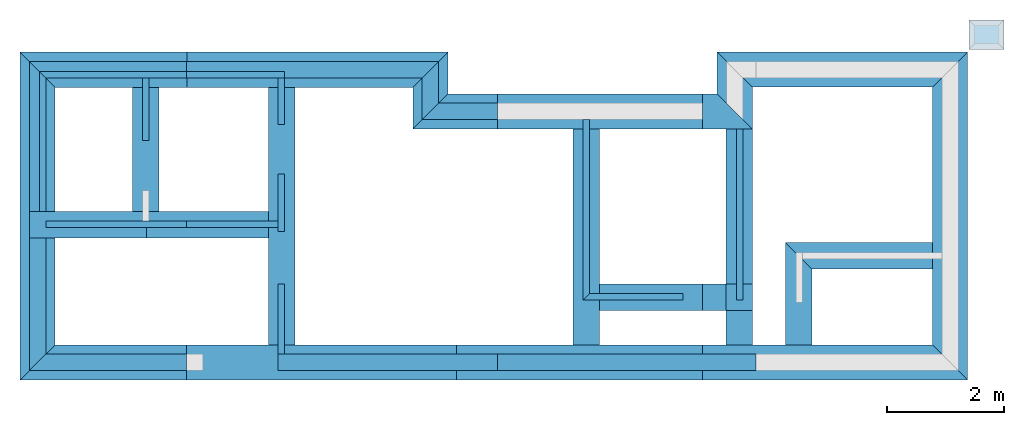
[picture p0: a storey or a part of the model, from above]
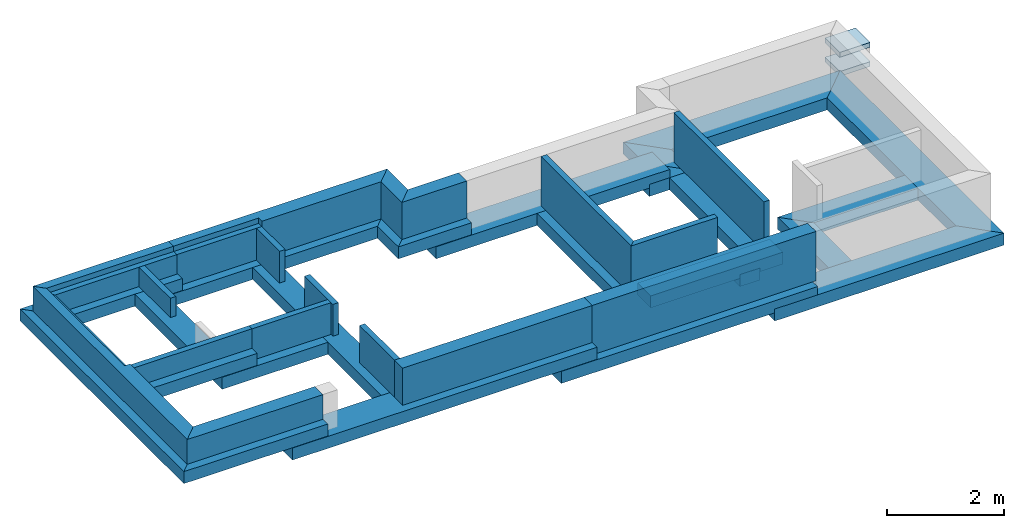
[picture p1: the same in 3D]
Properties of the parts of a building model (IFC2X3)

# File
Description: ViewDefinition [CoordinationView_V2.0], Option [Visible elements;Keep GUIDs;2D Elems;All Domain;All elements;All struct.;scale:100.000000;CSG:BREP;Junction:BREP;Comp. slab:BREPBuilding element parts;]
File name: /Users/johnm/Documents/Master/Projects/AIQS Costing Model/MOD Model/FINAL 2014/IFC Exports/Z01 Full Model.ifc
Time: 2014-02-20T13:36:24
Author: Architect
Organization: AUSTRALIAN INSTITUE OF QUANITY SURVEYERS
Written by: PreProc - EDM 5.0
Made in: IFC file generated by Graphisoft ArchiCAD-64 17.0.0 AUS FULL Macintosh version (IFC2x3 add-on version: 5019 AUS FULL).
Authorization: The authorising person

# IfcProject, Detailed Building Measurement
Phase: PRELIMINARY

# IfcSite, Lot 1. East Hills
RefLatitude: -33, -52, 0, 0; RefLongitude: 151, 13, 0, 0; RefElevation: 0 mm; LandTitleNumber: SP999999

# IfcBuildingStorey (4)
In: Proposed Units 7 & 8
Name | LongName | Elevation (mm)
Foundation | ACID00000002-0000-0000-0000-000000000000 | 1750
Ground | ACID00000003-0000-0000-0000-000000000000 | 3202
Level 1 | ACID00000004-0000-0000-0000-000000000000 | 5859
Roof | ACID00000005-0000-0000-0000-000000000000 | 8395

# IfcBeam: Concrete Reinforced 450 x 250 (10)
In: Foundation
Material: Concrete Reinforced
AC_Pset_RenovationAndPhasing - Renovation Status: Existing
Pset_BeamCommon - Reference: Concrete Reinforced 450 x 250
Name
2 x FT-TYP-A06 - Concrete Reinforced - Beam******************************
FT-TYP-A04 - Concrete Reinforced - Beam******************************
FT-TYP-A00 - Concrete Reinforced - Beam******************************
FT-TYP-A01 - Concrete Reinforced - Beam******************************
FT-TYP-A08 - Concrete Reinforced - Beam******************************
FT-TYP-A02 - Concrete Reinforced - Beam******************************
FT-TYP-A05 - Concrete Reinforced - Beam******************************
2 x FT-TYP-A07 - Concrete Reinforced - Beam******************************

# IfcBeam: Concrete Reinforced 50 x 104 (2)
In: Level 1
Material: Concrete Reinforced
AC_Pset_RenovationAndPhasing - Renovation Status: Existing
Pset_BeamCommon - Reference: Concrete Reinforced 50 x 104

# IfcBeam: Concrete Reinforced 600 x 250 (14)
In: Foundation
Material: Concrete Reinforced
AC_Pset_RenovationAndPhasing - Renovation Status: Existing
Pset_BeamCommon - Reference: Concrete Reinforced 600 x 250
Name
FT-TYP-A02 - Concrete Reinforced - Beam******************************
FT-TYP-A14 - Concrete Reinforced - Beam******************************
FT-TYP-A10 - Concrete Reinforced - Beam******************************
FT-TYP-B00 - Concrete Reinforced - Beam******************************
FT-TYP-B01 - Concrete Reinforced - Beam******************************
FT-TYP-B02 - Concrete Reinforced - Beam******************************
FT-TYP-B03 - Concrete Reinforced - Beam******************************
FT-TYP-B09 - Concrete Reinforced - Beam******************************
FT-TYP-B11 - Concrete Reinforced - Beam******************************
FT-TYP-B12 - Concrete Reinforced - Beam******************************
FT-TYP-B13 - Concrete Reinforced - Beam******************************
FT-TYP-A13 - Concrete Reinforced - Beam******************************
FT-TYP-A11 - Concrete Reinforced - Beam******************************
FT-TYP-A12 - Concrete Reinforced - Beam******************************

# IfcBeam: Purlin 12 (62)
Material: 50 %
AC_Pset_RenovationAndPhasing - Renovation Status: Existing
Pset_BeamCommon - LoadBearing: yes
Name | In | IsExternal
ROOF_BAT_29 - Purlin 12 - object - | Level 1 | yes
ROOF_BAT_01 - Purlin 12 - object - | Roof | no
ROOF_BAT_02 - Purlin 12 - object - | Roof | no
ROOF_BAT_03 - Purlin 12 - object - | Roof | no
ROOF_BAT_04 - Purlin 12 - object - | Roof | no
ROOF_BAT_05 - Purlin 12 - object - | Roof | no
ROOF_BAT_06 - Purlin 12 - object - | Roof | no
ROOF_BAT_07 - Purlin 12 - object - | Roof | no
ROOF_BAT_09 - Purlin 12 - object - | Roof | no
ROOF_BAT_10 - Purlin 12 - object - | Roof | no
ROOF_BAT_11 - Purlin 12 - object - | Roof | no
ROOF_BAT_12 - Purlin 12 - object - | Roof | no
ROOF_BAT_13 - Purlin 12 - object - | Roof | no
ROOF_BAT_14 - Purlin 12 - object - | Roof | no
ROOF_BAT_15 - Purlin 12 - object - | Roof | no
ROOF_BAT_16 - Purlin 12 - object - | Roof | no
ROOF_BAT_17 - Purlin 12 - object - | Roof | no
ROOF_BAT_18 - Purlin 12 - object - | Roof | no
ROOF_BAT_19 - Purlin 12 - object - | Roof | no
ROOF_BAT_20 - Purlin 12 - object - | Roof | no
ROOF_BAT_21 - Purlin 12 - object - | Roof | no
ROOF_BAT_22 - Purlin 12 - object - | Roof | no
ROOF_BAT_23 - Purlin 12 - object - | Roof | no
ROOF_BAT_24 - Purlin 12 - object - | Roof | no
ROOF_BAT_25 - Purlin 12 - object - | Roof | no
ROOF_BAT_26 - Purlin 12 - object - | Roof | no
ROOF_BAT_27 - Purlin 12 - object - | Roof | no
5 x ROOF_BAT_28 - Purlin 12 - object - | Roof | no
ROOF_BAT_29 - Purlin 12 - object - | Roof | yes
ROOF_BAT_30 - Purlin 12 - object - | Roof | no
ROOF_BAT_31 - Purlin 12 - object - | Roof | no
ROOF_BAT_32 - Purlin 12 - object - | Roof | no
ROOF_BAT_33 - Purlin 12 - object - | Roof | no
ROOF_BAT_34 - Purlin 12 - object - | Roof | no
ROOF_BAT_35 - Purlin 12 - object - | Roof | no
ROOF_BAT_36 - Purlin 12 - object - | Roof | no
ROOF_BAT_37 - Purlin 12 - object - | Roof | no
ROOF_BAT_38 - Purlin 12 - object - | Roof | no
ROOF_BAT_39 - Purlin 12 - object - | Roof | no
ROOF_BAT_40 - Purlin 12 - object - | Roof | no
ROOF_BAT_41 - Purlin 12 - object - | Roof | no
ROOF_BAT_42 - Purlin 12 - object - | Roof | no
ROOF_BAT_43 - Purlin 12 - object - | Roof | no
ROOF_BAT_44 - Purlin 12 - object - | Roof | no
ROOF_BAT_45 - Purlin 12 - object - | Roof | no
ROOF_BAT_46 - Purlin 12 - object - | Roof | no
ROOF_BAT_47 - Purlin 12 - object - | Roof | no
ROOF_BAT_48 - Purlin 12 - object - | Roof | no
ROOF_BAT_49 - Purlin 12 - object - | Roof | no
ROOF_BAT_50 - Purlin 12 - object - | Roof | no
ROOF_BAT_51 - Purlin 12 - object - | Roof | no
ROOF_BAT_52 - Purlin 12 - object - | Roof | no
ROOF_BAT_53 - Purlin 12 - object - | Roof | no
ROOF_BAT_54 - Purlin 12 - object - | Roof | no
ROOF_BAT_55 - Purlin 12 - object - | Roof | no
2 x ROOF_BAT_56 - Purlin 12 - object - | Roof | yes
ROOF_BAT_08 - Purlin 12 - object - | Roof | no

# IfcColumn: Concrete Reinforced D75 (2)
In: Level 1
Material: Concrete Reinforced
AC_Pset_RenovationAndPhasing - Renovation Status: Existing
Pset_ColumnCommon - Reference: Concrete Reinforced D75

# IfcCovering: CEILING BATTEN (10)
In: Ground
PredefinedType: CEILING; Material: 50 %
AC_Pset_RenovationAndPhasing - Renovation Status: Existing
Name
CEL-WALL-G06 - CEILING BATTEN - object -
CEL-WALL-G05 - CEILING BATTEN - object -
CEL-WALL-G09 - CEILING BATTEN - object -
CEL-WALL-G08 - CEILING BATTEN - object -
2 x CEL-BAT-GR05 - CEILING BATTEN - object -
CEL-WALL-G07 - CEILING BATTEN - object -
CEL-WALL-G02 - CEILING BATTEN - object -
CEL-WALL-G03 - CEILING BATTEN - object -
CEL-WALL-G01 - CEILING BATTEN - object -

# IfcCovering: CEILING BOARDS, CEL-COVER-G01 - CEILING BOARDS - object -
In: Ground
PredefinedType: CEILING; Material: 50 %
AC_Pset_RenovationAndPhasing - Renovation Status: Existing

# IfcCovering: CEILING BOARDS Level 1, TRUST_02 - CEILING BOARDS Level 1 - object -
In: Level 1
PredefinedType: CEILING; Material: 50 %
AC_Pset_RenovationAndPhasing - Renovation Status: Existing

# IfcCovering: EAVES FC LINNING, CEL-MOD-G39 - EAVES FC LINNING - object -
In: Level 1
PredefinedType: CEILING; Material: 50 %
AC_Pset_RenovationAndPhasing - Renovation Status: Existing

# IfcCovering: EAVES FC LINNING L1 (3)
PredefinedType: CEILING; Material: 50 %
AC_Pset_RenovationAndPhasing - Renovation Status: Existing
Name | In
CEL-MOD-G23 - EAVES FC LINNING L1 - object - | Ground
2 x EAVES COVERING - EAVES FC LINNING L1 - object - | Level 1

# IfcCovering: Molding Straight 12 (107)
Material: 50 %
AC_Pset_RenovationAndPhasing - Renovation Status: Existing
Name | In
CEL-MOD-G17 - Molding Straight 12 - object - | Ground
CEL-MOD-G34 - Molding Straight 12 - object - | Ground
CEL-MOD-G33 - Molding Straight 12 - object - | Ground
CEL-MOD-G32 - Molding Straight 12 - object - | Ground
CEL-MOD-G31 - Molding Straight 12 - object - | Ground
CEL-MOD-G30 - Molding Straight 12 - object - | Ground
CEL-MOD-G29 - Molding Straight 12 - object - | Ground
CEL-MOD-G28 - Molding Straight 12 - object - | Ground
CEL-MOD-G26 - Molding Straight 12 - object - | Ground
CEL-MOD-G25 - Molding Straight 12 - object - | Ground
CEL-MOD-G27 - Molding Straight 12 - object - | Ground
CEL-MOD-G24 - Molding Straight 12 - object - | Ground
CEL-MOD-G23 - Molding Straight 12 - object - | Ground
CEL-MOD-G22 - Molding Straight 12 - object - | Ground
CEL-MOD-G21 - Molding Straight 12 - object - | Ground
CEL-MOD-G20 - Molding Straight 12 - object - | Ground
CEL-MOD-G19 - Molding Straight 12 - object - | Ground
CEL-MOD-G18 - Molding Straight 12 - object - | Ground
CEL-MOD-G16 - Molding Straight 12 - object - | Ground
CEL-MOD-G15 - Molding Straight 12 - object - | Ground
7 x U2_HANDBASIN - Molding Straight 12 - object - | Ground
CEL-MOD-G12 - Molding Straight 12 - object - | Ground
CEL-MOD-G11 - Molding Straight 12 - object - | Ground
CEL-MOD-G09 - Molding Straight 12 - object - | Ground
CEL-MOD-G07 - Molding Straight 12 - object - | Ground
CEL-MOD-G06 - Molding Straight 12 - object - | Ground
CEL-MOD-G05 - Molding Straight 12 - object - | Ground
CEL-MOD-G02 - Molding Straight 12 - object - | Ground
19 x Sk_01 - Molding Straight 12 - object - | Ground
CEL_MOD_134 - Molding Straight 12 - object - | Level 1
CEL_MOD_133 - Molding Straight 12 - object - | Level 1
CEL_MOD_132 - Molding Straight 12 - object - | Level 1
CEL_MOD_131 - Molding Straight 12 - object - | Level 1
CEL_MOD_130 - Molding Straight 12 - object - | Level 1
CEL_MOD_129 - Molding Straight 12 - object - | Level 1
CEL_MOD_128 - Molding Straight 12 - object - | Level 1
CEL_MOD_127 - Molding Straight 12 - object - | Level 1
CEL_MOD_126 - Molding Straight 12 - object - | Level 1
CEL_MOD_125 - Molding Straight 12 - object - | Level 1
CEL_MOD_124 - Molding Straight 12 - object - | Level 1
CEL_MOD_123 - Molding Straight 12 - object - | Level 1
CEL_MOD_122 - Molding Straight 12 - object - | Level 1
CEL_MOD_121 - Molding Straight 12 - object - | Level 1
CEL_MOD_120 - Molding Straight 12 - object - | Level 1
CEL_MOD_119 - Molding Straight 12 - object - | Level 1
CEL_MOD_118 - Molding Straight 12 - object - | Level 1
CEL_MOD_117 - Molding Straight 12 - object - | Level 1
CEL_MOD_116 - Molding Straight 12 - object - | Level 1
CEL_MOD_115 - Molding Straight 12 - object - | Level 1
CEL_MOD_114 - Molding Straight 12 - object - | Level 1
CEL_MOD_113 - Molding Straight 12 - object - | Level 1
CEL_MOD_112 - Molding Straight 12 - object - | Level 1
CEL_MOD_111 - Molding Straight 12 - object - | Level 1
CEL_MOD_110 - Molding Straight 12 - object - | Level 1
CEL_MOD_109 - Molding Straight 12 - object - | Level 1
CEL_MOD_108 - Molding Straight 12 - object - | Level 1
CEL_MOD_107 - Molding Straight 12 - object - | Level 1
CEL_MOD_106 - Molding Straight 12 - object - | Level 1
CEL_MOD_105 - Molding Straight 12 - object - | Level 1
CEL_MOD_104 - Molding Straight 12 - object - | Level 1
CEL_MOD_103 - Molding Straight 12 - object - | Level 1
CEL_MOD_102 - Molding Straight 12 - object - | Level 1
CEL_MOD_101 - Molding Straight 12 - object - | Level 1
20 x Sk_01 - Molding Straight 12 - object - | Level 1

# IfcDiscreteAccessory: Block Inclined 12 (6)
In: Roof
Material: 50 %
AC_Pset_RenovationAndPhasing - Renovation Status: Existing

# IfcDiscreteAccessory: Purlin 12, ROOF_BAT_29 - Purlin 12 - object -
In: Level 1
Material: 50 %
AC_Pset_RenovationAndPhasing - Renovation Status: Existing

# IfcDistributionElement: Downspout Complex 12 (3)
In: Level 1
Material: 50 %
AC_Pset_RenovationAndPhasing - Renovation Status: Existing

# IfcDistributionElement: gutter (3)
In: Roof
Material: 50 %
AC_Pset_RenovationAndPhasing - Renovation Status: Existing

# IfcDoor: D1 12, 15 D1 12 0.85 x 2.067 x 1 Door
In: Level 1
Type - OperationType: SINGLE_SWING_LEFT; ParameterTakesPrecedence: no; Sizeable: no
Type - Door Lining Properties - LiningDepth: 100 mm; LiningThickness: 30 mm; ThresholdDepth: 10 mm; ThresholdThickness: 12 mm
Type - Door Panel Properties - Panel 1 - PanelDepth: 35 mm; PanelOperation: SWINGING; PanelWidth: 0.964706; PanelPosition: MIDDLE
OverallHeight: 2067 mm; OverallWidth: 850 mm; Material: Empty Fill (8), air space
AC_Pset_RenovationAndPhasing - Renovation Status: Existing

# IfcDoor: D1 12, 9 D1 12 0.78 x 2.067 x 1 Door
In: Level 1
Type - OperationType: SINGLE_SWING_LEFT; ParameterTakesPrecedence: no; Sizeable: no
Type - Door Lining Properties - LiningDepth: 100 mm; LiningThickness: 50 mm; ThresholdDepth: 10 mm; ThresholdThickness: 12 mm
Type - Door Panel Properties - Panel 1 - PanelDepth: 35 mm; PanelOperation: SWINGING; PanelWidth: 0.910256; PanelPosition: MIDDLE
OverallHeight: 2067 mm; OverallWidth: 780 mm; Material: Empty Fill (8), air space
AC_Pset_RenovationAndPhasing - Renovation Status: Existing

# IfcDoor: D1 12 (5)
Type - OperationType: SINGLE_SWING_LEFT; ParameterTakesPrecedence: no; Sizeable: no
Type - Door Lining Properties - LiningDepth: 115 mm; LiningThickness: 15 mm; ThresholdDepth: 10 mm; ThresholdThickness: 12 mm
Type - Door Panel Properties - Panel 1 - PanelDepth: 35 mm; PanelOperation: SWINGING; PanelWidth: 0.964706; PanelPosition: MIDDLE
OverallHeight: 2067 mm; OverallWidth: 850 mm; Material: Empty Fill (8), air space
AC_Pset_RenovationAndPhasing - Renovation Status: Existing
Name | In
2 D1 12 0.85 x 2.067 x 1 Door | Ground
7 D1 12 0.85 x 2.067 x 1 Door | Ground
5 D1 12 0.85 x 2.067 x 1 Door | Ground
14 D1 12 0.85 x 2.067 x 1 Door | Level 1
12 D1 12 0.85 x 2.067 x 1 Door | Level 1

# IfcDoor: D1 12 (2)
Type - OperationType: SINGLE_SWING_RIGHT; ParameterTakesPrecedence: no; Sizeable: no
Type - Door Lining Properties - LiningDepth: 115 mm; LiningThickness: 15 mm; ThresholdDepth: 10 mm; ThresholdThickness: 12 mm
Type - Door Panel Properties - Panel 1 - PanelDepth: 35 mm; PanelOperation: SWINGING; PanelWidth: 0.964706; PanelPosition: MIDDLE
OverallHeight: 2067 mm; OverallWidth: 850 mm; Material: Empty Fill (8), air space
AC_Pset_RenovationAndPhasing - Renovation Status: Existing
Name | In
6 D1 12 0.85 x 2.067 x 1 Door | Ground
13 D1 12 0.85 x 2.067 x 1 Door | Level 1

# IfcDoor: D1 12, 8 D1 12 0.85 x 2.067 x 1 Door
In: Level 1
Type - OperationType: SINGLE_SWING_RIGHT; ParameterTakesPrecedence: no; Sizeable: no
Type - Door Lining Properties - LiningDepth: 115 mm; LiningThickness: 30 mm; ThresholdDepth: 10 mm; ThresholdThickness: 12 mm
Type - Door Panel Properties - Panel 1 - PanelDepth: 45 mm; PanelOperation: SWINGING; PanelWidth: 0.964706; PanelPosition: MIDDLE
OverallHeight: 2067 mm; OverallWidth: 850 mm; Material: Empty Fill (8), air space
AC_Pset_RenovationAndPhasing - Renovation Status: Existing

# IfcDoor: D1 Entrance side1 12, 1 D1 Entrance side1 12 1.28 x 2.067 x 1 Door
In: Ground
Type - OperationType: SINGLE_SWING_LEFT; ParameterTakesPrecedence: no; Sizeable: no
Type - Door Lining Properties - LiningDepth: 100 mm; LiningThickness: 75 mm; ThresholdDepth: 10 mm; ThresholdThickness: 12 mm
Type - Door Panel Properties - Panel 1 - PanelDepth: 40 mm; PanelOperation: SWINGING; PanelWidth: 0.640625; PanelPosition: MIDDLE
OverallHeight: 2067 mm; OverallWidth: 1280 mm; Material: Empty Fill (9), air space
AC_Pset_RenovationAndPhasing - Renovation Status: Existing

# IfcDoor: D1 Sliding Ext 11 (2)
Type - OperationType: SLIDING_TO_LEFT; ParameterTakesPrecedence: no; Sizeable: no
Type - Door Lining Properties - LiningThickness: 50 mm; ThresholdThickness: 12 mm
Type - Door Panel Properties - Panel 1 - PanelDepth: 35 mm; PanelOperation: SLIDING; PanelWidth: 0.882353; PanelPosition: MIDDLE
OverallHeight: 2067 mm; OverallWidth: 850 mm; Material: Empty Fill (9)
AC_Pset_RenovationAndPhasing - Renovation Status: Existing
Name | In
4 D1 Sliding Ext 11 0.85 x 2.067 x 1 Door | Ground
11 D1 Sliding Ext 11 0.85 x 2.067 x 1 Door | Level 1

# IfcDoor: D1 Sliding Ext 11, 10 D1 Sliding Ext 11 0.85 x 2.067 x 1 Door
In: Level 1
Type - OperationType: SLIDING_TO_RIGHT; ParameterTakesPrecedence: no; Sizeable: no
Type - Door Lining Properties - LiningThickness: 50 mm; ThresholdThickness: 12 mm
Type - Door Panel Properties - Panel 1 - PanelDepth: 35 mm; PanelOperation: SLIDING; PanelWidth: 0.882353; PanelPosition: MIDDLE
OverallHeight: 2067 mm; OverallWidth: 850 mm; Material: Empty Fill (9)
AC_Pset_RenovationAndPhasing - Renovation Status: Existing

# IfcDoor: D1 Sliding Ext 11, 3 D1 Sliding Ext 11 0.85 x 2.067 x 1 Door
In: Ground
Type - OperationType: SLIDING_TO_RIGHT; ParameterTakesPrecedence: no; Sizeable: no
Type - Door Lining Properties - LiningThickness: 50 mm; ThresholdThickness: 12 mm
Type - Door Panel Properties - Panel 1 - PanelDepth: 40 mm; PanelOperation: SLIDING; PanelWidth: 0.882353; PanelPosition: MIDDLE
OverallHeight: 2067 mm; OverallWidth: 850 mm; Material: Empty Fill (9)
AC_Pset_RenovationAndPhasing - Renovation Status: Existing

# IfcDoor: D2 Sliding 12, D003 D2 Sliding 12 1.81 x 2.067 x 1 Door
In: Ground
Type - OperationType: SLIDING_TO_LEFT; ParameterTakesPrecedence: no; Sizeable: no
Type - Door Lining Properties - LiningDepth: 100 mm; LiningThickness: 30 mm; ThresholdThickness: 12 mm
Type - Door Panel Properties - Panel 1 - PanelDepth: 40 mm; PanelOperation: SLIDING; PanelWidth: 0.966851; PanelPosition: MIDDLE
OverallHeight: 2067 mm; OverallWidth: 1810 mm; Material: Empty Fill (8), air space
AC_Pset_RenovationAndPhasing - Renovation Status: Existing

# IfcFurnishingElement: Cabinet Base Cooktop+Oven 12 (2)
Material: 50 %
AC_Pset_RenovationAndPhasing - Renovation Status: Existing
Name | In
COOKTOP_G0_T - Cabinet Base Cooktop+Oven 12 - object - | Ground
COOKTOP_G0_T - Cabinet Base Cooktop+Oven 12 - object - | Level 1

# IfcFurnishingElement: Cupboard 12 (4)
Material: 50 %
AC_Pset_RenovationAndPhasing - Renovation Status: Existing
Name | In
U1_HANDBASIN - Cupboard 12 - object - | Ground
U7_WAR02 - Cupboard 12 - object - | Ground
U7_WAR02 - Cupboard 12 - object - | Level 1
CAB_L1_01 - Cupboard 12 - object - | Level 1

# IfcFurnishingElement: Refrigerator 12 (2)
Material: 50 %
AC_Pset_RenovationAndPhasing - Renovation Status: Existing
Name | In
U7_FRIDGE - Refrigerator 12 - object - | Ground
U7_FRIDGE - Refrigerator 12 - object - | Level 1

# IfcRailing: Railing Vertical 12, BALU - Railing Vertical 12 - object -
In: Level 1
Material: 50 %
AC_Pset_RenovationAndPhasing - Renovation Status: Existing

# IfcSlab: Battens for Roof Tiles 12 (6)
PredefinedType: ROOF; Material: 50 %
AC_Pset_RenovationAndPhasing - Renovation Status: Existing
Pset_SlabCommon - IsExternal: yes
Name | In | LoadBearing
2 x BATTEN_01 - Battens for Roof Tiles 12 - object - | Level 1 | yes
BATTEN_02 - Battens for Roof Tiles 12 - object - | Roof | yes
2 x BATTEN_01 - Battens for Roof Tiles 12 - object - | Roof | yes
BATTEN_02 - Battens for Roof Tiles 12 - object - | Roof

# IfcSlab: Concrete Reinforced 100 (9)
Type - PredefinedType: FLOOR
Material: Concrete Reinforced 100 mm
AC_Pset_RenovationAndPhasing - Renovation Status: Existing
Name | In
2 x Slab-G09 Concrete Reinforced Slab | Foundation
6 x Slab-G02 Concrete Reinforced Slab | Ground
Slab-G04 Concrete Reinforced Slab | Ground

# IfcSlab: Concrete Reinforced 110 (4)
Type - PredefinedType: FLOOR
Material: Concrete Reinforced 110 mm
AC_Pset_RenovationAndPhasing - Renovation Status: Existing
Name | In
Slab-G01 Concrete Reinforced Slab | Ground
Slab-G03 Concrete Reinforced Slab | Ground
2 x Slab002 Concrete Reinforced Slab | Level 1

# IfcSlab: Concrete Reinforced 150 (2)
In: Level 1
Type - PredefinedType: FLOOR
AC_Pset_RenovationAndPhasing - Renovation Status: Existing
Name | Material
Slab002 Concrete Reinforced Slab | Concrete Reinforced
Slab002 Concrete Reinforced Slab | Concrete Reinforced 150 mm

# IfcSlab: Concrete Reinforced 200, Slab-G08 Concrete Reinforced Slab
In: Ground
Type - PredefinedType: FLOOR
Material: Concrete Reinforced 200 mm
AC_Pset_RenovationAndPhasing - Renovation Status: Existing

# IfcSlab: Concrete Reinforced 300 (4)
In: Ground
Type - PredefinedType: FLOOR
Material: Concrete Reinforced 300 mm
AC_Pset_RenovationAndPhasing - Renovation Status: Existing
Name
2 x Slab-G06 Concrete Reinforced Slab
2 x Slab-G05 Concrete Reinforced Slab

# IfcSlab: Gravel 22 (4)
Type - PredefinedType: ROOF
Material: Gravel 21.6506 mm
AC_Pset_RenovationAndPhasing - Renovation Status: Existing
Name | In
2 x Roof002 Gravel Roof | Level 1
2 x Roof002 Gravel Roof | Roof

# IfcSlab: Gravel 24, Roof001 Gravel Roof
In: Roof
PredefinedType: ROOF; Material: Gravel 24.1481 mm
AC_Pset_RenovationAndPhasing - Renovation Status: Existing
Pset_SlabCommon - IsExternal: yes

# IfcSlab: Purlin 12 (13)
In: Level 1
PredefinedType: ROOF; Material: 50 %
AC_Pset_RenovationAndPhasing - Renovation Status: Existing
Pset_SlabCommon - LoadBearing: yes; IsExternal: yes
Name
5 x ROOF_BAT_27 - Purlin 12 - object -
ROOF_BAT_26 - Purlin 12 - object -
2 x ROOF_BAT_25 - Purlin 12 - object -
ROOF_BAT_24 - Purlin 12 - object -
ROOF_BAT_23 - Purlin 12 - object -
ROOF_BAT_22 - Purlin 12 - object -
ROOF_BAT_21 - Purlin 12 - object -
ROOF_BAT_08 - Purlin 12 - object -

# IfcSlab: Roof Trust large (27)
In: Roof
PredefinedType: ROOF; Material: 50 %
AC_Pset_RenovationAndPhasing - Renovation Status: Existing
Pset_SlabCommon - LoadBearing: yes; IsExternal: yes
Name
TRUST_01 - Roof Trust large - object -
TRUST_02 - Roof Trust large - object -
TRUST_03 - Roof Trust large - object -
TRUST_04 - Roof Trust large - object -
TRUST_05 - Roof Trust large - object -
TRUST_06 - Roof Trust large - object -
TRUST_07 - Roof Trust large - object -
TRUST_08 - Roof Trust large - object -
TRUST_09 - Roof Trust large - object -
TRUST_10 - Roof Trust large - object -
TRUST_11 - Roof Trust large - object -
TRUST_12 - Roof Trust large - object -
TRUST_13 - Roof Trust large - object -
TRUST_14 - Roof Trust large - object -
TRUST_15 - Roof Trust large - object -
TRUST_16 - Roof Trust large - object -
TRUST_17 - Roof Trust large - object -
TRUST_18 - Roof Trust large - object -
TRUST_19 - Roof Trust large - object -
TRUST_20 - Roof Trust large - object -
TRUST_21 - Roof Trust large - object -
TRUST_22 - Roof Trust large - object -
TRUST_23 - Roof Trust large - object -
TRUST_24 - Roof Trust large - object -
TRUST_25 - Roof Trust large - object -
TRUST_26 - Roof Trust large - object -
TRUST_27 - Roof Trust large - object -

# IfcSlab: Strut 2 12 (13)
In: Level 1
PredefinedType: ROOF; Material: 50 %
AC_Pset_RenovationAndPhasing - Renovation Status: Existing
Pset_SlabCommon - LoadBearing: yes; IsExternal: yes

# IfcStair (2)
Material: 50 %
AC_Pset_RenovationAndPhasing - Renovation Status: Existing
Name | In
Stair007 - Stair Straight RC 12 - object - | Ground
Stair007 - Stair Straight RC 12 - object - | Level 1

# IfcWall: Cavity wall 280 295 (20)
Material: Brickwork Faced (2), Cavity, Cement Render
AC_Pset_RenovationAndPhasing - Renovation Status: Existing
Name | In | LoadBearing | IsExternal
2 x EXT-WALL-G10 Cavity wall 280 Wall | Ground | yes | no
EXT-WALL-G08 Cavity wall 280 Wall | Ground | yes | yes
EXT-WALL-G06 Cavity wall 280 Wall | Ground | yes | yes
EXT-WALL-GH09 Cavity wall 280 Wall | Ground
EXT-WALL-G02 Cavity wall 280 Wall | Ground | yes | yes
EXT-WALL-G04 Cavity wall 280 Wall | Ground | yes | yes
EXT-WALL-G09 Cavity wall 280 Wall | Ground | yes | no
EXT-WALL-G01 Cavity wall 280 Wall | Ground | yes | yes
EXT-WALL-G03 Cavity wall 280 Wall | Ground | yes | yes
EXT-WALL-G07 Cavity wall 280 Wall | Ground | yes | yes
EXT-WALL-G05 Cavity wall 280 Wall | Ground | yes | yes
EXT-WALL-104 Cavity wall 280 Wall | Level 1 | yes | no
EXT-WALL-102 Cavity wall 280 Wall | Level 1 | yes | no
EXT-WALL-100 Cavity wall 280 Wall | Level 1 | yes | no
EXT-WALL-101 Cavity wall 280 Wall | Level 1 | yes | no
EXT-WALL-103 Cavity wall 280 Wall | Level 1 | yes | no
EXT-WALL-105 Cavity wall 280 Wall | Level 1 | yes | no
EXT-WALL-106 Cavity wall 280 Wall | Level 1 | yes | no
EXT-WALL-107 Cavity wall 280 Wall | Level 1 | yes | no

# IfcWall: Cavity wall 280 Foundation 280 (15)
In: Foundation
Material: Brickwork Faced, Cavity, Brick Common
AC_Pset_RenovationAndPhasing - Renovation Status: Existing
Pset_WallCommon - LoadBearing: yes; IsExternal: yes
Name
RET-WALL-F06 Cavity wall 280 Foundation Wall
RET-WALL-F05 Cavity wall 280 Foundation Wall
RET-WALL-F03 Cavity wall 280 Foundation Wall
RET-WALL-F00 Cavity wall 280 Foundation Wall
RET-WALL-F11 Cavity wall 280 Foundation Wall
RET-WALL-F13 Cavity wall 280 Foundation Wall
RET-WALL-F02 Cavity wall 280 Foundation Wall
2 x RET-WALL-F07 Cavity wall 280 Foundation Wall
RET-WALL-F12 Cavity wall 280 Foundation Wall
RET-WALL-F01 Cavity wall 280 Foundation Wall
RET-WALL-F08 Cavity wall 280 Foundation Wall
RET-WALL-F04 Cavity wall 280 Foundation Wall
RET-WALL-F09 Cavity wall 280 Foundation Wall
RET-WALL-F10 Cavity wall 280 Foundation Wall

# IfcWall: Cavity wall @slab 0017047810 170 (7)
In: Ground
Material: Brickwork Faced, Cavity
AC_Pset_RenovationAndPhasing - Renovation Status: Existing
Name
4 x EXT-WALL-GH05 Cavity wall @slab 0017047810 Wall
EXT-WALL-GH03 Cavity wall @slab 0017047810 Wall
EXT-WALL-GH08 Cavity wall @slab 0017047810 Wall
EXT-WALL-GH06 Cavity wall @slab 0017047810 Wall

# IfcWall: Cavity wall @slab 170 (4)
In: Ground
Material: Brickwork Faced, Cavity
AC_Pset_RenovationAndPhasing - Renovation Status: Existing
Name
EXT-WALL-GH01 Cavity wall @slab Wall
EXT-WALL-GH02 Cavity wall @slab Wall
EXT-WALL-GH04 Cavity wall @slab Wall
EXT-WALL-GH07 Cavity wall @slab Wall

# IfcWall: Concrete Block 140 140 (4)
In: Level 1
Material: Concrete Block
AC_Pset_RenovationAndPhasing - Renovation Status: Existing
Name
2 x Wall008 Concrete Block 140 Wall
Wall009 Concrete Block 140 Wall
Wall007 Concrete Block 140 Wall

# IfcWall: Empty Fill 100 (4)
In: Foundation
Material: Empty Fill
AC_Pset_RenovationAndPhasing - Renovation Status: Existing
Name
Wall011 Empty Fill Wall
Wall008 Empty Fill Wall
Wall009 Empty Fill Wall
Wall010 Empty Fill Wall

# IfcWall: Empty Fill 13 (9)
Material: Empty Fill
AC_Pset_RenovationAndPhasing - Renovation Status: Existing
Name | In
Wall008 Empty Fill Wall | Ground
4 x Wall007 Empty Fill Wall | Ground
4 x Wall007 Empty Fill Wall | Level 1

# IfcWall: Empty Fill 35 (3)
In: Level 1
Material: Empty Fill
AC_Pset_RenovationAndPhasing - Renovation Status: Existing

# IfcWall: Solid Brick Foundation 110 (11)
In: Foundation
Material: Brick Common
AC_Pset_RenovationAndPhasing - Renovation Status: Existing
Pset_WallCommon - LoadBearing: yes; IsExternal: no
Name
4 x INT-WALLG02 Solid Brick Foundation Wall
3 x INT-WALLG03 Solid Brick Foundation Wall
INT-WALLG04 Solid Brick Foundation Wall
INT-WALLG05 Solid Brick Foundation Wall
INT-WALLG06 Solid Brick Foundation Wall
INT-WALLG07 Solid Brick Foundation Wall

# IfcWall: Solid Brick Render Both Side 140 140 (18)
Material: Cement Render (2), Brickwork Faced
AC_Pset_RenovationAndPhasing - Renovation Status: Existing
Pset_WallCommon - LoadBearing: yes; IsExternal: no
Name | In
INT-WALLG00 Solid Brick Render Both Side 140 Wall | Ground
INT-WALLG01 Solid Brick Render Both Side 140 Wall | Ground
INT-WALLG02 Solid Brick Render Both Side 140 Wall | Ground
INT-WALLG06 Solid Brick Render Both Side 140 Wall | Ground
INT-WALLG07 Solid Brick Render Both Side 140 Wall | Ground
INT-WALLG03 Solid Brick Render Both Side 140 Wall | Ground
INT-WALLG04 Solid Brick Render Both Side 140 Wall | Ground
INT-WALLG05 Solid Brick Render Both Side 140 Wall | Ground
3 x Wall007 Solid Brick Render Both Side 140 Wall | Level 1
5 x Wall006 Solid Brick Render Both Side 140 Wall | Level 1
2 x Wall008 Solid Brick Render Both Side 140 Wall | Level 1

# IfcWall: Timber Stud 20 (3)
In: Roof
Material: Timber Stud
AC_Pset_RenovationAndPhasing - Renovation Status: Existing
Pset_WallCommon - LoadBearing: yes; IsExternal: yes

# IfcWall: bULKHEAD FRAMING (3)
In: Ground
Material: 50 %
AC_Pset_RenovationAndPhasing - Renovation Status: Existing

# IfcWallStandardCase: Empty Fill 35, Wall006 Empty Fill Wall
In: Level 1
Material: Empty Fill 35 mm
AC_Pset_RenovationAndPhasing - Renovation Status: Existing

# IfcWallStandardCase: Solid Brick Foundation 110, INT-WALLG07 Solid Brick Foundation Wall
In: Foundation
Material: Brick Common 110 mm
AC_Pset_RenovationAndPhasing - Renovation Status: Existing
Pset_WallCommon - LoadBearing: yes; IsExternal: no

# IfcWindow: W Single Hung 1 11 (2)
In: Ground
Type - OperationType: SINGLE_PANEL; ParameterTakesPrecedence: no; Sizeable: no
Type - Window Lining Properties - LiningDepth: 50 mm; LiningThickness: 50 mm
Type - Window Panel Properties - Panel 1 - PanelPosition: MIDDLE; FrameDepth: 25 mm; FrameThickness: 50 mm
Material: Empty Fill (9), air space
AC_Pset_RenovationAndPhasing - Renovation Status: Existing
Name | OverallHeight (mm) | OverallWidth (mm)
W008 W Single Hung 1 11 0.9 x 1.467 Window | 1467 | 900
W006 W Single Hung 1 11 0.85 x 1.982 Window | 1982 | 850

# IfcWindow: W2 Horizontal Slide 11 (15)
Type - OperationType: DOUBLE_PANEL_VERTICAL; ParameterTakesPrecedence: no; Sizeable: no
Type - Window Lining Properties - LiningDepth: 50 mm; LiningThickness: 50 mm
Type - Window Panel Properties - Panel 1 - PanelPosition: LEFT
Type - Window Panel Properties - Panel 2 - PanelPosition: RIGHT
Material: Empty Fill (9), air space
AC_Pset_RenovationAndPhasing - Renovation Status: Existing
Name | In | OverallHeight (mm) | OverallWidth (mm)
2 x W001 W2 Horizontal Slide 11 1.21 x 1.038 Window | Ground | 1038 | 1210
W003 W2 Horizontal Slide 11 1.81 x 1.467 Window | Ground | 1467 | 1810
W004 W2 Horizontal Slide 11 1.81 x 1.467 Window | Ground | 1467 | 1810
W005 W2 Horizontal Slide 11 1.81 x 1.467 Window | Ground | 1467 | 1810
W008 W2 Horizontal Slide 11 1.81 x 1.467 Window | Ground | 1467 | 1810
W007 W2 Horizontal Slide 11 1.21 x 0.696 Window | Ground | 696 | 1210
W002 W2 Horizontal Slide 11 1.81 x 1.457 Window | Level 1 | 1457 | 1810
2 x W001 W2 Horizontal Slide 11 1.21 x 1.02 Window | Level 1 | 1020 | 1210
W003 W2 Horizontal Slide 11 1.81 x 1.457 Window | Level 1 | 1457 | 1810
W004 W2 Horizontal Slide 11 1.81 x 1.457 Window | Level 1 | 1457 | 1810
W005 W2 Horizontal Slide 11 1.81 x 1.457 Window | Level 1 | 1457 | 1810
W008 W2 Horizontal Slide 11 1.81 x 1.457 Window | Level 1 | 1457 | 1810
W007 W2 Horizontal Slide 11 1.21 x 0.685 Window | Level 1 | 685 | 1210
